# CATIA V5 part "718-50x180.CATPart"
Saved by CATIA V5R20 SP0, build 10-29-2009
Part number: 718-50x180
Definition: NONE
Nomenclature: 718-50x180
Source: Unknown
Description: 718-50x180
Bounding box of the stored display mesh (mm): x 0 to 227, y -31.5 to 31.5, z -31.5 to 31.5
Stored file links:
  C:\Users\Utente\Desktop\IO LAVORO\3D X SITO CF\X SITO\718\718-50x180.CATPart

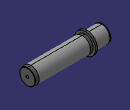
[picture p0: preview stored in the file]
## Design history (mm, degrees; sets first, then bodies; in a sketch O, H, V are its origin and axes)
Body1 "718-50x180" (main body)
  Solid1: solid without history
